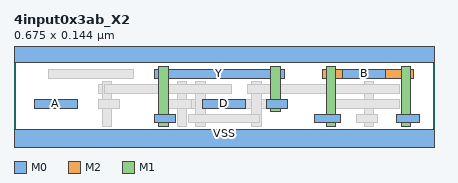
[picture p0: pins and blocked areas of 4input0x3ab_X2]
MACRO 4input0x3ab_X2
  CLASS CORE ;
  ORIGIN 0 0 ;
  FOREIGN 4input0x3ab_X2 0 0 ;
  SIZE 0.6750 BY 0.1440 ;
  SYMMETRY X Y ;
  SITE coresite ;
  PIN A
    DIRECTION INPUT ;
    USE SIGNAL ;
    PORT
      LAYER M0 ;
        RECT 0.0330 0.0530 0.1020 0.0670 ;
    END
  END A
  PIN B
    DIRECTION INPUT ;
    USE SIGNAL ;
    PORT
      LAYER M0 ;
        RECT 0.5280 0.1010 0.5970 0.1150 ;
    END
  END B
  PIN C
    DIRECTION INPUT ;
    USE SIGNAL ;
    PORT
      LAYER M2 ;
        RECT 0.4950 0.1010 0.6420 0.1150 ;
      LAYER M1 ;
        RECT 0.5025 0.0240 0.5175 0.1200 ;
        RECT 0.6225 0.0240 0.6375 0.1200 ;
      LAYER M0 ;
        RECT 0.6150 0.0290 0.6525 0.0430 ;
        RECT 0.4830 0.0290 0.5250 0.0430 ;
    END
  END C
  PIN D
    DIRECTION INPUT ;
    USE SIGNAL ;
    PORT
      LAYER M0 ;
        RECT 0.3030 0.0530 0.3720 0.0670 ;
    END
  END D
  PIN Y
    DIRECTION OUTPUT ;
    USE SIGNAL ;
    PORT
      LAYER M1 ;
        RECT 0.2325 0.0240 0.2475 0.1200 ;
        RECT 0.4125 0.0480 0.4275 0.1200 ;
      LAYER M0 ;
        RECT 0.2250 0.1010 0.4350 0.1150 ;
        RECT 0.2250 0.0290 0.2595 0.0430 ;
        RECT 0.4050 0.0530 0.4395 0.0670 ;
    END
  END Y
  PIN VDD
    DIRECTION INOUT ;
    USE POWER ;
    SHAPE ABUTMENT ;
    PORT
      LAYER M0 ;
        RECT 0.0000 0.1260 0.6750 0.1620 ;
    END
  END VDD
  PIN VSS
    DIRECTION INOUT ;
    USE GROUND ;
    SHAPE ABUTMENT ;
    PORT
      LAYER M0 ;
        RECT 0.0000 -0.0180 0.6750 0.0180 ;
    END
  END VSS
  OBS
    LAYER M2 ;
      RECT 0.2580 0.0530 0.4050 0.0670 ;
      RECT 0.1350 0.0770 0.3150 0.0910 ;
    LAYER V1 ;
      RECT 0.5030 0.1010 0.5170 0.1150 ;
      RECT 0.6230 0.1010 0.6370 0.1150 ;
      RECT 0.1430 0.0770 0.1570 0.0910 ;
      RECT 0.2930 0.0770 0.3070 0.0910 ;
      RECT 0.2630 0.0530 0.2770 0.0670 ;
      RECT 0.3830 0.0530 0.3970 0.0670 ;
    LAYER M1 ;
      RECT 0.1425 0.0240 0.1575 0.0960 ;
      RECT 0.2625 0.0240 0.2775 0.0960 ;
      RECT 0.2925 0.0240 0.3075 0.0960 ;
      RECT 0.3825 0.0240 0.3975 0.0960 ;
      RECT 0.5625 0.0240 0.5775 0.0960 ;
    LAYER V0 ;
      RECT 0.5030 0.0290 0.5170 0.0430 ;
      RECT 0.6230 0.0290 0.6370 0.0430 ;
      RECT 0.1430 0.0530 0.1570 0.0670 ;
      RECT 0.2930 0.0290 0.3070 0.0430 ;
      RECT 0.2630 0.0530 0.2770 0.0670 ;
      RECT 0.3830 0.0770 0.3970 0.0910 ;
      RECT 0.5630 0.0770 0.5770 0.0910 ;
      RECT 0.5630 0.0290 0.5770 0.0430 ;
      RECT 0.2330 0.1010 0.2470 0.1150 ;
      RECT 0.2330 0.0290 0.2470 0.0430 ;
      RECT 0.4130 0.1010 0.4270 0.1150 ;
      RECT 0.4130 0.0530 0.4270 0.0670 ;
    LAYER M0 ;
      RECT 0.2805 0.0290 0.3945 0.0430 ;
      RECT 0.5505 0.0290 0.5850 0.0430 ;
      RECT 0.1350 0.0530 0.1695 0.0670 ;
      RECT 0.2475 0.0530 0.2850 0.0670 ;
      RECT 0.5055 0.0530 0.6195 0.0670 ;
      RECT 0.1455 0.0770 0.3495 0.0910 ;
      RECT 0.3750 0.0770 0.6195 0.0910 ;
      RECT 0.0555 0.1010 0.1920 0.1150 ;
  END
END 4input0x3ab_X2
